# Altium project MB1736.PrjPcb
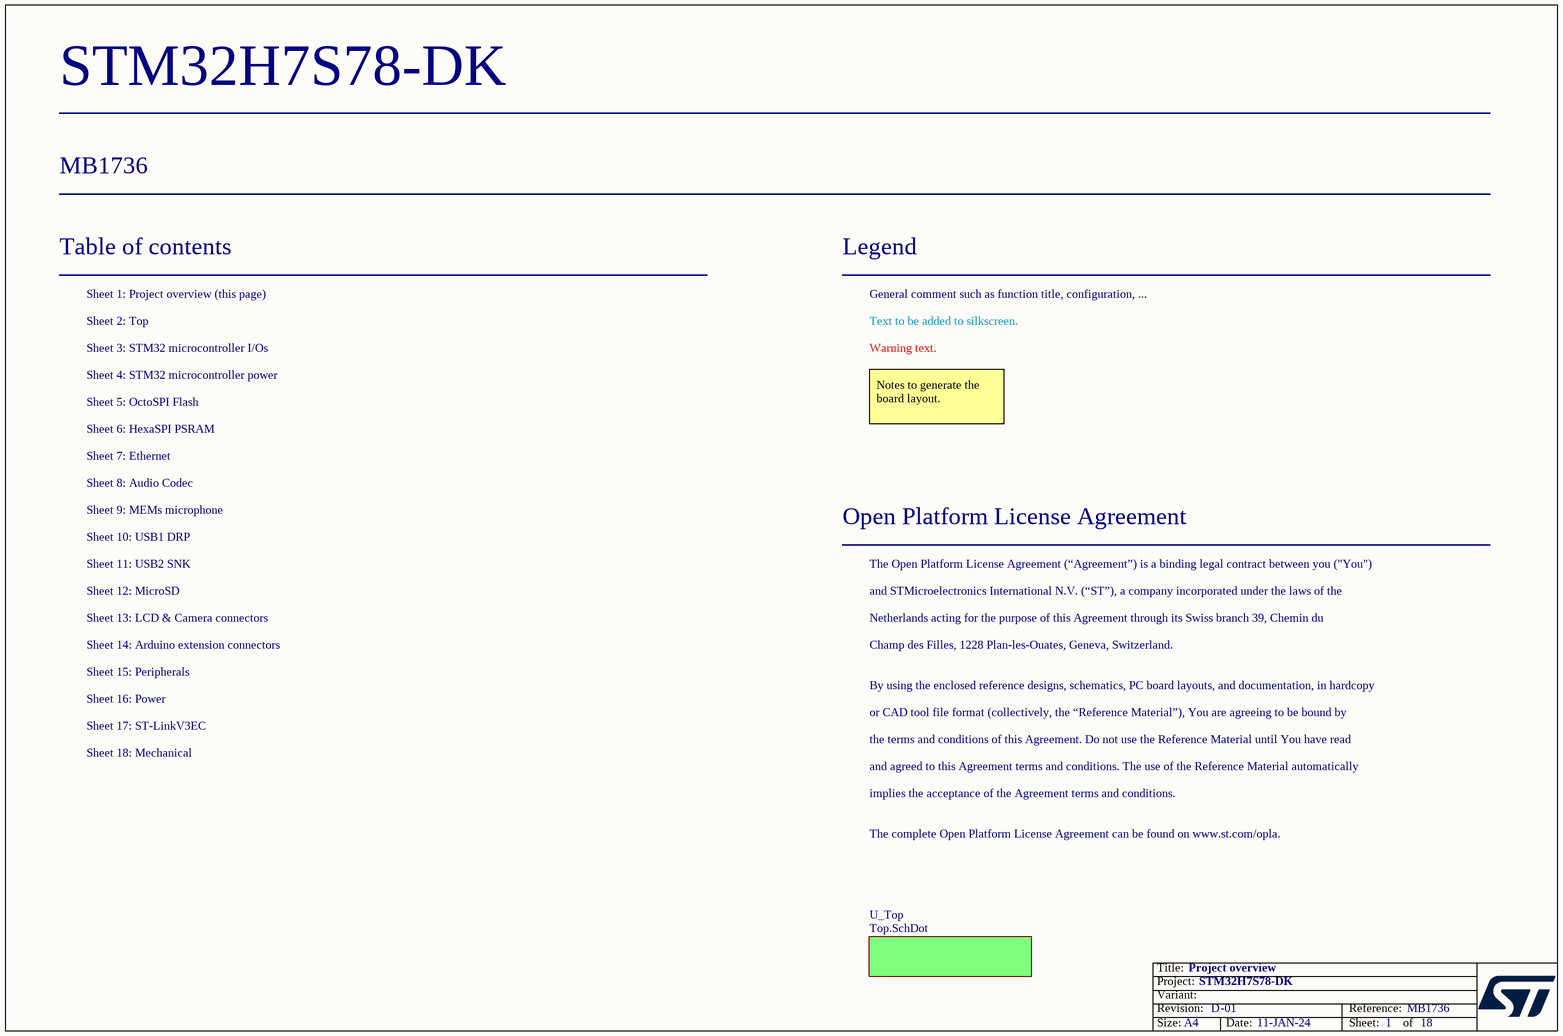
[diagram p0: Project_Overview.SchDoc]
Board_Reference: MB1736; Board_PCB_Revision: D; Board_Name: STM32H7S78-DK; Board_Document_Date: 11-JAN-24; Board_Assembly_Revision: 01
1 sheet, 0 parts. Net scope: global (net labels, ports and power ports of the same name join across sheets).
Board file: MB1736.PcbDoc

## Sheet Project_Overview.SchDoc: Project overview
size A4; Date: Not used; ApprovedBy: Not used; CheckedBy: Not used; Author: Not used; CompanyName: STMicroelectronics; DrawnBy: Not used; Engineer: Not used; Organization: Not used; Address1: Not used; Address2: Not used; Address3: Not used; Address4: Not used; DocumentNumber: Not used; Revision: Not used; SheetNumber: 1; SheetTotal: 18

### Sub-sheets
U_Top = Top.SchDot (file not in this document): no entries

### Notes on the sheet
- Table of contents
- Sheet 1: Project overview (this page)
- Legend
- General comment such as function title, configuration, ...
- Sheet 2: Top
- Sheet 3: STM32 microcontroller I/Os
- Sheet 4: STM32 microcontroller power
- Text to be added to silkscreen.
- Warning text.
- Sheet 5: OctoSPI Flash
- Sheet 6: HexaSPI PSRAM
- Notes to generate the board layout.
- Sheet 7: Ethernet
- Sheet 8: Audio Codec
- Sheet 9: MEMs microphone
- Sheet 10: USB1 DRP
- Sheet 11: USB2 SNK
- Open Platform License Agreement
- The Open Platform License Agreement (“Agreement”) is a binding legal contract between you ("You")
- Sheet 14: Arduino extension connectors
- Sheet 12: MicroSD
- Sheet 13: LCD & Camera connectors
- and STMicroelectronics International N.V. (“ST”), a company incorporated under the laws of the
- Netherlands acting for the purpose of this Agreement through its Swiss branch 39, Chemin du
- Champ des Filles, 1228 Plan-les-Ouates, Geneva, Switzerland.
- Sheet 16: Power
- Sheet 15: Peripherals
- By using the enclosed reference designs, schematics, PC board layouts, and documentation, in hardcopy
- or CAD tool file format (collectively, the “Reference Material”), You are agreeing to be bound by
- Sheet 17: ST-LinkV3EC
- Sheet 18: Mechanical
- the terms and conditions of this Agreement. Do not use the Reference Material until You have read
- and agreed to this Agreement terms and conditions. The use of the Reference Material automatically
- implies the acceptance of the Agreement terms and conditions.
- The complete Open Platform License Agreement can be found on www.st.com/opla.

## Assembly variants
H7S7L8: not fitted C4 C80 C81 C83 C89 C90 C138 C139 C157 CN5 CN9 CN19 HW8 R9 R66 R68 R83 R84 R117 R120 SB1 SB3 SB5 SB7 SB10 SB11 SB13 SB15 SB17 SB19 SB24 SB27 SB32 SB39 SB43 SB45 SB47 SB52 SB65 SB72 SB73 SB74 SB75 SB76 SB77 U2 U12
